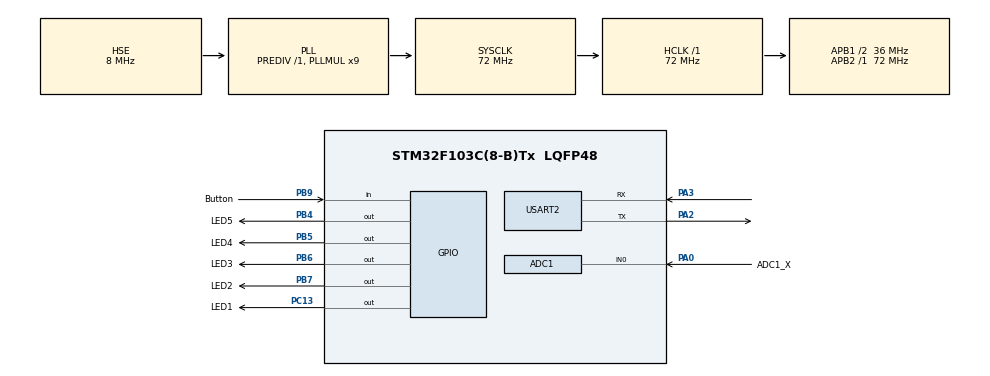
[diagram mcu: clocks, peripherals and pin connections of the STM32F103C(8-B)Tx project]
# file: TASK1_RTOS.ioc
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ADC1.Channel-1\#ChannelRegularConversion=ADC_CHANNEL_0
ADC1.NbrOfConversionFlag=1
ADC1.Rank-1\#ChannelRegularConversion=1
ADC1.SamplingTime-1\#ChannelRegularConversion=ADC_SAMPLETIME_1CYCLE_5
ADC1.master=1
FREERTOS.Tasks01=defaultTask,24,128,StartDefaultTask,Default,NULL,Dynamic,NULL,NULL;pickButtonTask,8,128,pickButton,Default,NULL,Dynamic,NULL,NULL;getADCTask,32,128,getADC,Default,NULL,Dynamic,NULL,NULL;dispLEDTask,24,128,dispLED,Default,NULL,Dynamic,NULL,NULL;dispUARTTask,24,128,dispUART,Default,NULL,Dynamic,NULL,NULL
FREERTOS.configTOTAL_HEAP_SIZE=3600
FREERTOS.configUSE_NEWLIB_REENTRANT=1
Mcu.Family=STM32F1
Mcu.Name=STM32F103C(8-B)Tx
Mcu.Package=LQFP48
NVIC.PriorityGroup=NVIC_PRIORITYGROUP_4
NVIC.TIM4_IRQn=true\:15\:0\:false\:false\:true\:false\:false\:true\:true
NVIC.TimeBase=TIM4_IRQn
NVIC.TimeBaseIP=TIM4
PA0-WKUP.GPIO_Label=ADC1_X
PA0-WKUP.Signal=ADCx_IN0
PA13.Mode=Serial_Wire
PA13.Signal=SYS_JTMS-SWDIO
PA14.Mode=Serial_Wire
PA14.Signal=SYS_JTCK-SWCLK
PA2.Mode=Asynchronous
PA2.Signal=USART2_TX
PA3.Mode=Asynchronous
PA3.Signal=USART2_RX
PB4.GPIO_Label=LED5
PB4.PinState=GPIO_PIN_RESET
PB4.Signal=GPIO_Output
PB5.GPIO_Label=LED4
PB5.PinState=GPIO_PIN_RESET
PB5.Signal=GPIO_Output
PB6.GPIO_Label=LED3
PB6.Signal=GPIO_Output
PB7.GPIO_Label=LED2
PB7.Signal=GPIO_Output
PB9.GPIO_Label=Button
PB9.GPIO_PuPd=GPIO_PULLUP
PB9.Signal=GPIO_Input
PC13-TAMPER-RTC.GPIO_Label=LED1
PC13-TAMPER-RTC.Signal=GPIO_Output
PD0-OSC_IN.Mode=HSE-External-Oscillator
PD0-OSC_IN.Signal=RCC_OSC_IN
PD1-OSC_OUT.Mode=HSE-External-Oscillator
PD1-OSC_OUT.Signal=RCC_OSC_OUT
ProjectManager.HeapSize=0x200
ProjectManager.StackSize=0x400
ProjectManager.TargetToolchain=STM32CubeIDE
RCC.ADCPresc=RCC_ADCPCLK2_DIV6
RCC.AHBFreq_Value=72000000
RCC.APB1CLKDivider=RCC_HCLK_DIV2
RCC.APB1Freq_Value=36000000
RCC.APB1TimFreq_Value=72000000
RCC.APB2Freq_Value=72000000
RCC.APB2TimFreq_Value=72000000
RCC.HCLKFreq_Value=72000000
RCC.PLLMUL=RCC_PLL_MUL9
RCC.PLLSourceVirtual=RCC_PLLSOURCE_HSE
RCC.SYSCLKFreq_VALUE=72000000
RCC.SYSCLKSource=RCC_SYSCLKSOURCE_PLLCLK
RCC.USBFreq_Value=72000000
SH.ADCx_IN0.0=ADC1_IN0,IN0
USART2.VirtualMode=VM_ASYNC
VP_FREERTOS_VS_CMSIS_V2.Mode=CMSIS_V2
VP_SYS_VS_tim4.Mode=TIM4
board=custom

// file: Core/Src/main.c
/* USER CODE BEGIN Header */
/**
  ******************************************************************************
  * @file           : main.c
  * @brief          : Main program body
  ******************************************************************************
  * @attention
  *
  * Copyright (c) 2024 STMicroelectronics.
  * All rights reserved.
  *
  * This software is licensed under terms that can be found in the LICENSE file
  * in the root directory of this software component.
  * If no LICENSE file comes with this software, it is provided AS-IS.
  *
  ******************************************************************************
  */
/* USER CODE END Header */
#include "main.h"
#include "cmsis_os.h"

ADC_HandleTypeDef hadc1;

UART_HandleTypeDef huart2;

/* Definitions for defaultTask */
osThreadId_t defaultTaskHandle;
const osThreadAttr_t defaultTask_attributes = {
  .name = "defaultTask",
  .stack_size = 128 * 4,
  .priority = (osPriority_t) osPriorityNormal,
};
/* Definitions for pickButtonTask */
osThreadId_t pickButtonTaskHandle;
const osThreadAttr_t pickButtonTask_attributes = {
  .name = "pickButtonTask",
  .stack_size = 128 * 4,
  .priority = (osPriority_t) osPriorityLow,
};
/* Definitions for getADCTask */
osThreadId_t getADCTaskHandle;
const osThreadAttr_t getADCTask_attributes = {
  .name = "getADCTask",
  .stack_size = 128 * 4,
  .priority = (osPriority_t) osPriorityAboveNormal,
};
/* Definitions for dispLEDTask */
osThreadId_t dispLEDTaskHandle;
const osThreadAttr_t dispLEDTask_attributes = {
  .name = "dispLEDTask",
  .stack_size = 128 * 4,
  .priority = (osPriority_t) osPriorityNormal,
};
/* Definitions for dispUARTTask */
osThreadId_t dispUARTTaskHandle;
const osThreadAttr_t dispUARTTask_attributes = {
  .name = "dispUARTTask",
  .stack_size = 128 * 4,
  .priority = (osPriority_t) osPriorityNormal,
};

void SystemClock_Config(void);
static void MX_GPIO_Init(void);
static void MX_ADC1_Init(void);
static void MX_USART2_UART_Init(void);
void StartDefaultTask(void *argument);
void pickButton(void *argument);
void getADC(void *argument);
void dispLED(void *argument);
void dispUART(void *argument);

/* USER CODE BEGIN PFP */

int button_pressed, x_val;
char buffer[17];
char buffer2[25];
uint8_t choice;
void Menu_Display (){
	sprintf(buffer2, "press 1 to show ADC value");
	HAL_UART_Transmit(&huart2, buffer2, sizeof(buffer2), 24);
}

void Light_LED(){
	if(x_val < 4096/5){
			HAL_GPIO_WritePin(LED1_GPIO_Port, LED1_Pin, 1);
			HAL_GPIO_WritePin(LED2_GPIO_Port, LED2_Pin, 0);
			HAL_GPIO_WritePin(LED3_GPIO_Port, LED3_Pin, 0);
			HAL_GPIO_WritePin(LED4_GPIO_Port, LED4_Pin, 0);
			HAL_GPIO_WritePin(LED5_GPIO_Port, LED5_Pin, 0);
		} else if(x_val < 4096*2/5){
			HAL_GPIO_WritePin(LED1_GPIO_Port, LED1_Pin, 1);
			HAL_GPIO_WritePin(LED2_GPIO_Port, LED2_Pin, 1);
			HAL_GPIO_WritePin(LED3_GPIO_Port, LED3_Pin, 0);
			HAL_GPIO_WritePin(LED4_GPIO_Port, LED4_Pin, 0);
			HAL_GPIO_WritePin(LED5_GPIO_Port, LED5_Pin, 0);
		} else if(x_val < 4096*3/5){
			HAL_GPIO_WritePin(LED1_GPIO_Port, LED1_Pin, 1);
			HAL_GPIO_WritePin(LED2_GPIO_Port, LED2_Pin, 1);
			HAL_GPIO_WritePin(LED3_GPIO_Port, LED3_Pin, 1);
			HAL_GPIO_WritePin(LED4_GPIO_Port, LED4_Pin, 0);
			HAL_GPIO_WritePin(LED5_GPIO_Port, LED5_Pin, 0);
		} else if(x_val < 4096*4/5){
			HAL_GPIO_WritePin(LED1_GPIO_Port, LED1_Pin, 1);
			HAL_GPIO_WritePin(LED2_GPIO_Port, LED2_Pin, 1);
			HAL_GPIO_WritePin(LED3_GPIO_Port, LED3_Pin, 1);
			HAL_GPIO_WritePin(LED4_GPIO_Port, LED4_Pin, 1);
			HAL_GPIO_WritePin(LED5_GPIO_Port, LED5_Pin, 0);
		} else{
			HAL_GPIO_WritePin(LED1_GPIO_Port, LED1_Pin, 1);
			HAL_GPIO_WritePin(LED2_GPIO_Port, LED2_Pin, 1);
			HAL_GPIO_WritePin(LED3_GPIO_Port, LED3_Pin, 1);
			HAL_GPIO_WritePin(LED4_GPIO_Port, LED4_Pin, 1);
			HAL_GPIO_WritePin(LED5_GPIO_Port, LED5_Pin, 1);
		}
}

/* USER CODE END PFP */

int main(void)
{

  /* MCU Configuration--------------------------------------------------------*/

  /* Reset of all peripherals, Initializes the Flash interface and the Systick. */
  HAL_Init();

  /* Configure the system clock */
  SystemClock_Config();

  /* Initialize all configured peripherals */
  MX_GPIO_Init();
  MX_ADC1_Init();
  MX_USART2_UART_Init();

  /* Init scheduler */
  osKernelInitialize();

  /* Create the thread(s) */
  /* creation of defaultTask */
  defaultTaskHandle = osThreadNew(StartDefaultTask, NULL, &defaultTask_attributes);

  /* creation of pickButtonTask */
  pickButtonTaskHandle = osThreadNew(pickButton, NULL, &pickButtonTask_attributes);

  /* creation of getADCTask */
  getADCTaskHandle = osThreadNew(getADC, NULL, &getADCTask_attributes);

  /* creation of dispLEDTask */
  dispLEDTaskHandle = osThreadNew(dispLED, NULL, &dispLEDTask_attributes);

  /* creation of dispUARTTask */
  dispUARTTaskHandle = osThreadNew(dispUART, NULL, &dispUARTTask_attributes);

  /* Start scheduler */
  osKernelStart();

  /* We should never get here as control is now taken by the scheduler */

  /* Infinite loop */
  while (1)
  {

  }
}

void SystemClock_Config(void)
{
  RCC_OscInitTypeDef RCC_OscInitStruct = {0};
  RCC_ClkInitTypeDef RCC_ClkInitStruct = {0};
  RCC_PeriphCLKInitTypeDef PeriphClkInit = {0};

  /** Initializes the RCC Oscillators according to the specified parameters
  * in the RCC_OscInitTypeDef structure.
  */
  RCC_OscInitStruct.OscillatorType = RCC_OSCILLATORTYPE_HSE;
  RCC_OscInitStruct.HSEState = RCC_HSE_ON;
  RCC_OscInitStruct.HSEPredivValue = RCC_HSE_PREDIV_DIV1;
  RCC_OscInitStruct.HSIState = RCC_HSI_ON;
  RCC_OscInitStruct.PLL.PLLState = RCC_PLL_ON;
  RCC_OscInitStruct.PLL.PLLSource = RCC_PLLSOURCE_HSE;
  RCC_OscInitStruct.PLL.PLLMUL = RCC_PLL_MUL9;
  if (HAL_RCC_OscConfig(&RCC_OscInitStruct) != HAL_OK)
  {
    Error_Handler();
  }

  /** Initializes the CPU, AHB and APB buses clocks
  */
  RCC_ClkInitStruct.ClockType = RCC_CLOCKTYPE_HCLK|RCC_CLOCKTYPE_SYSCLK
                              |RCC_CLOCKTYPE_PCLK1|RCC_CLOCKTYPE_PCLK2;
  RCC_ClkInitStruct.SYSCLKSource = RCC_SYSCLKSOURCE_PLLCLK;
  RCC_ClkInitStruct.AHBCLKDivider = RCC_SYSCLK_DIV1;
  RCC_ClkInitStruct.APB1CLKDivider = RCC_HCLK_DIV2;
  RCC_ClkInitStruct.APB2CLKDivider = RCC_HCLK_DIV1;

  if (HAL_RCC_ClockConfig(&RCC_ClkInitStruct, FLASH_LATENCY_2) != HAL_OK)
  {
    Error_Handler();
  }
  PeriphClkInit.PeriphClockSelection = RCC_PERIPHCLK_ADC;
  PeriphClkInit.AdcClockSelection = RCC_ADCPCLK2_DIV6;
  if (HAL_RCCEx_PeriphCLKConfig(&PeriphClkInit) != HAL_OK)
  {
    Error_Handler();
  }
}

static void MX_ADC1_Init(void)
{

  ADC_ChannelConfTypeDef sConfig = {0};

  /** Common config
  */
  hadc1.Instance = ADC1;
  hadc1.Init.ScanConvMode = ADC_SCAN_DISABLE;
  hadc1.Init.ContinuousConvMode = DISABLE;
  hadc1.Init.DiscontinuousConvMode = DISABLE;
  hadc1.Init.ExternalTrigConv = ADC_SOFTWARE_START;
  hadc1.Init.DataAlign = ADC_DATAALIGN_RIGHT;
  hadc1.Init.NbrOfConversion = 1;
  if (HAL_ADC_Init(&hadc1) != HAL_OK)
  {
    Error_Handler();
  }

  /** Configure Regular Channel
  */
  sConfig.Channel = ADC_CHANNEL_0;
  sConfig.Rank = ADC_REGULAR_RANK_1;
  sConfig.SamplingTime = ADC_SAMPLETIME_1CYCLE_5;
  if (HAL_ADC_ConfigChannel(&hadc1, &sConfig) != HAL_OK)
  {
    Error_Handler();
  }

}

static void MX_USART2_UART_Init(void)
{

  huart2.Instance = USART2;
  huart2.Init.BaudRate = 115200;
  huart2.Init.WordLength = UART_WORDLENGTH_8B;
  huart2.Init.StopBits = UART_STOPBITS_1;
  huart2.Init.Parity = UART_PARITY_NONE;
  huart2.Init.Mode = UART_MODE_TX_RX;
  huart2.Init.HwFlowCtl = UART_HWCONTROL_NONE;
  huart2.Init.OverSampling = UART_OVERSAMPLING_16;
  if (HAL_UART_Init(&huart2) != HAL_OK)
  {
    Error_Handler();
  }

}

static void MX_GPIO_Init(void)
{
  GPIO_InitTypeDef GPIO_InitStruct = {0};

  /* GPIO Ports Clock Enable */
  __HAL_RCC_GPIOC_CLK_ENABLE();
  __HAL_RCC_GPIOD_CLK_ENABLE();
  __HAL_RCC_GPIOA_CLK_ENABLE();
  __HAL_RCC_GPIOB_CLK_ENABLE();

  /*Configure GPIO pin Output Level */
  HAL_GPIO_WritePin(LED1_GPIO_Port, LED1_Pin, GPIO_PIN_RESET);

  /*Configure GPIO pin Output Level */
  HAL_GPIO_WritePin(GPIOB, LED5_Pin|LED4_Pin|LED3_Pin|LED2_Pin, GPIO_PIN_RESET);

  /*Configure GPIO pin : LED1_Pin */
  GPIO_InitStruct.Pin = LED1_Pin;
  GPIO_InitStruct.Mode = GPIO_MODE_OUTPUT_PP;
  GPIO_InitStruct.Pull = GPIO_NOPULL;
  GPIO_InitStruct.Speed = GPIO_SPEED_FREQ_LOW;
  HAL_GPIO_Init(LED1_GPIO_Port, &GPIO_InitStruct);

  /*Configure GPIO pin : PA9 */
  GPIO_InitStruct.Pin = GPIO_PIN_9;
  GPIO_InitStruct.Mode = GPIO_MODE_AF_PP;
  GPIO_InitStruct.Speed = GPIO_SPEED_FREQ_HIGH;
  HAL_GPIO_Init(GPIOA, &GPIO_InitStruct);

  /*Configure GPIO pin : PA10 */
  GPIO_InitStruct.Pin = GPIO_PIN_10;
  GPIO_InitStruct.Mode = GPIO_MODE_INPUT;
  GPIO_InitStruct.Pull = GPIO_NOPULL;
  HAL_GPIO_Init(GPIOA, &GPIO_InitStruct);

  /*Configure GPIO pins : LED5_Pin LED4_Pin LED3_Pin LED2_Pin */
  GPIO_InitStruct.Pin = LED5_Pin|LED4_Pin|LED3_Pin|LED2_Pin;
  GPIO_InitStruct.Mode = GPIO_MODE_OUTPUT_PP;
  GPIO_InitStruct.Pull = GPIO_NOPULL;
  GPIO_InitStruct.Speed = GPIO_SPEED_FREQ_LOW;
  HAL_GPIO_Init(GPIOB, &GPIO_InitStruct);

  /*Configure GPIO pin : Button_Pin */
  GPIO_InitStruct.Pin = Button_Pin;
  GPIO_InitStruct.Mode = GPIO_MODE_INPUT;
  GPIO_InitStruct.Pull = GPIO_PULLUP;
  HAL_GPIO_Init(Button_GPIO_Port, &GPIO_InitStruct);

}

void StartDefaultTask(void *argument)
{
  for(;;)
  {
    osDelay(1);
  }
}

void pickButton(void *argument)
{
  /* USER CODE BEGIN pickButton */
  /* Infinite loop */
  for(;;)
  {

	  if(HAL_GPIO_ReadPin(Button_GPIO_Port, Button_Pin) == GPIO_PIN_RESET)
	  {
		  osDelay(300);	// debounce
		  button_pressed = 1;
	  }

    osDelay(100);
  }
  /* USER CODE END pickButton */
}

void getADC(void *argument)
{
  /* USER CODE BEGIN getADC */
  /* Infinite loop */
  for(;;)
  {

	  HAL_ADC_Start(&hadc1);
	  HAL_ADC_PollForConversion(&hadc1, 10);
	  x_val = (HAL_ADC_GetValue(&hadc1));
	  HAL_ADC_Stop(&hadc1);

	  // process ADC values here

    osDelay(100);
  }
  /* USER CODE END getADC */
}

void dispLED(void *argument)
{
  /* USER CODE BEGIN dispLED */
  /* Infinite loop */
  for(;;)
  {
	  if (button_pressed) {
		  Light_LED();
	  }
	  else {
		  HAL_GPIO_WritePin(LED1_GPIO_Port, LED1_Pin, 0);
		  HAL_GPIO_WritePin(LED2_GPIO_Port, LED2_Pin, 0);
		  HAL_GPIO_WritePin(LED3_GPIO_Port, LED3_Pin, 0);
		  HAL_GPIO_WritePin(LED4_GPIO_Port, LED4_Pin, 0);
		  HAL_GPIO_WritePin(LED5_GPIO_Port, LED5_Pin, 0);
	  }
    osDelay(1);
  }
  /* USER CODE END dispLED */
}

void dispUART(void *argument)
{
  /* USER CODE BEGIN dispUART */
  /* Infinite loop */
	Menu_Display();

		  for(;;)
		  {
			  // select user input
			  if (HAL_UART_Receive(&huart2, &choice, sizeof(choice), 1) == HAL_OK)
			  {
				switch (choice) {

					case '1':
						//HAL_UART_Transmit(&huart1, (uint8_t*)"2 pressed\r\n", sizeof("1 pressed\r\n"), 10);
						sprintf(buffer, "Voltage = %d\r\n",x_val);
						HAL_UART_Transmit(&huart2, buffer, sizeof(buffer), 16);
						break;
					case '2':
						Menu_Display();
						break;
					default:
						break;
				}
			  }else{

			  }

			  if(button_pressed)
			  {
				  HAL_UART_Transmit(&huart2, (uint8_t*)"Button1 pressed\r\n", sizeof("Button1 pressed\r\n"), 30);
				  button_pressed = 0;
			  }
			  osDelay(100);
		  }
  /* USER CODE END dispUART */
}

void HAL_TIM_PeriodElapsedCallback(TIM_HandleTypeDef *htim)
{
  if (htim->Instance == TIM4) {
    HAL_IncTick();
  }
}

void Error_Handler(void)
{
  __disable_irq();
  while (1)
  {
  }
}
